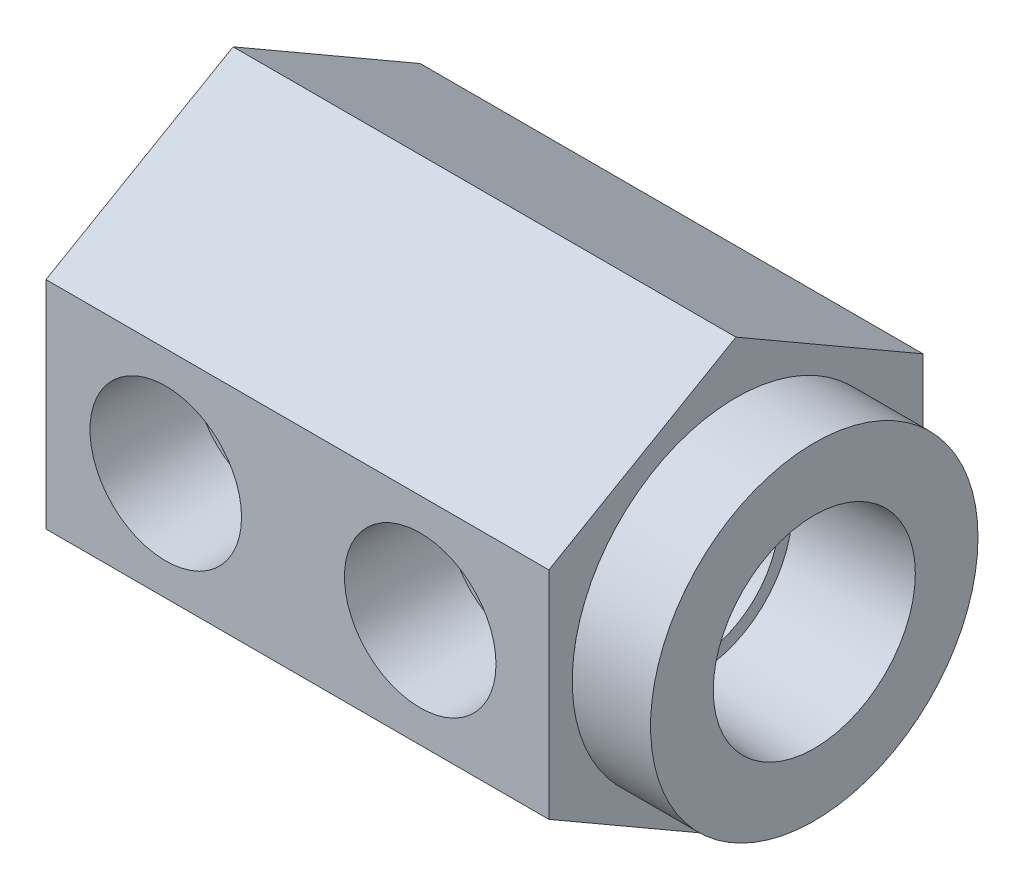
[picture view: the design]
ISO-10303-21;
HEADER;
FILE_DESCRIPTION(('STEP AP214'),'2;1');
FILE_NAME('part.step','',(''),(''),'','','');
FILE_SCHEMA(('AUTOMOTIVE_DESIGN { 1 0 10303 214 1 1 1 1 }'));
ENDSEC;
DATA;
#1=APPLICATION_CONTEXT('core data for automotive mechanical design processes');
#2=APPLICATION_PROTOCOL_DEFINITION('international standard','automotive_design',2000,#1);
#3=PRODUCT_CONTEXT('',#1,'mechanical');
#4=PRODUCT('Part','Part','',(#3));
#5=PRODUCT_RELATED_PRODUCT_CATEGORY('part','',(#4));
#6=PRODUCT_DEFINITION_FORMATION('','',#4);
#7=PRODUCT_DEFINITION_CONTEXT('part definition',#1,'design');
#8=PRODUCT_DEFINITION('design','',#6,#7);
#9=PRODUCT_DEFINITION_SHAPE('','',#8);
#10=(LENGTH_UNIT() NAMED_UNIT(*) SI_UNIT(.MILLI.,.METRE.));
#11=(NAMED_UNIT(*) PLANE_ANGLE_UNIT() SI_UNIT($,.RADIAN.));
#12=(NAMED_UNIT(*) SI_UNIT($,.STERADIAN.) SOLID_ANGLE_UNIT());
#13=UNCERTAINTY_MEASURE_WITH_UNIT(LENGTH_MEASURE(1.E-05),#10,'distance_accuracy_value','');
#14=(GEOMETRIC_REPRESENTATION_CONTEXT(3) GLOBAL_UNCERTAINTY_ASSIGNED_CONTEXT((#13)) GLOBAL_UNIT_ASSIGNED_CONTEXT((#10,
#11,#12)) REPRESENTATION_CONTEXT('',''));
#15=CARTESIAN_POINT('',(0.,0.,0.));
#16=DIRECTION('',(0.,0.,1.));
#17=DIRECTION('',(1.,0.,0.));
#18=AXIS2_PLACEMENT_3D('',#15,#16,#17);
#19=CARTESIAN_POINT('',(39.44747,0.,0.));
#20=DIRECTION('',(1.,0.,0.));
#21=DIRECTION('',(0.,0.,-1.));
#22=AXIS2_PLACEMENT_3D('',#19,#20,#21);
#23=PLANE('',#22);
#24=CARTESIAN_POINT('',(39.44747,0.,0.));
#25=DIRECTION('',(1.,0.,0.));
#26=DIRECTION('',(0.,0.,-1.));
#27=AXIS2_PLACEMENT_3D('',#24,#25,#26);
#28=CIRCLE('',#27,11.1125);
#29=CARTESIAN_POINT('',(39.44747,0.,-11.1125));
#30=VERTEX_POINT('',#29);
#31=EDGE_CURVE('E137',#30,#30,#28,.T.);
#32=ORIENTED_EDGE('',*,*,#31,.T.);
#33=EDGE_LOOP('',(#32));
#34=FACE_BOUND('',#33,.T.);
#35=CARTESIAN_POINT('',(39.44747,0.,0.));
#36=DIRECTION('',(-1.,0.,0.));
#37=DIRECTION('',(0.,0.,1.));
#38=AXIS2_PLACEMENT_3D('',#35,#36,#37);
#39=CIRCLE('',#38,6.85806655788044);
#40=CARTESIAN_POINT('',(39.44747,0.,6.85806655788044));
#41=VERTEX_POINT('',#40);
#42=EDGE_CURVE('E292',#41,#41,#39,.T.);
#43=ORIENTED_EDGE('',*,*,#42,.T.);
#44=EDGE_LOOP('',(#43));
#45=FACE_BOUND('',#44,.T.);
#46=ADVANCED_FACE('F35',(#34,#45),#23,.T.);
#47=CARTESIAN_POINT('',(34.13125,-7.33234841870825,12.7));
#48=DIRECTION('',(1.,0.,0.));
#49=DIRECTION('',(0.,0.,-1.));
#50=AXIS2_PLACEMENT_3D('',#47,#48,#49);
#51=PLANE('',#50);
#52=DIRECTION('',(0.,-1.,0.));
#53=VECTOR('',#52,1.);
#54=CARTESIAN_POINT('',(34.13125,7.33234841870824,12.7));
#55=LINE('',#54,#53);
#56=CARTESIAN_POINT('',(34.13125,7.33234841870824,12.7));
#57=VERTEX_POINT('',#56);
#58=CARTESIAN_POINT('',(34.13125,-7.33234841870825,12.7));
#59=VERTEX_POINT('',#58);
#60=EDGE_CURVE('E145',#57,#59,#55,.T.);
#61=ORIENTED_EDGE('',*,*,#60,.T.);
#62=DIRECTION('',(0.,-0.5,-0.866025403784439));
#63=VECTOR('',#62,1.);
#64=CARTESIAN_POINT('',(34.13125,-7.33234841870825,12.7));
#65=LINE('',#64,#63);
#66=CARTESIAN_POINT('',(34.13125,-14.6646968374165,0.));
#67=VERTEX_POINT('',#66);
#68=EDGE_CURVE('E95',#59,#67,#65,.T.);
#69=ORIENTED_EDGE('',*,*,#68,.T.);
#70=DIRECTION('',(0.,0.5,-0.866025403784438));
#71=VECTOR('',#70,1.);
#72=CARTESIAN_POINT('',(34.13125,-14.6646968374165,0.));
#73=LINE('',#72,#71);
#74=CARTESIAN_POINT('',(34.13125,-7.33234841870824,-12.7));
#75=VERTEX_POINT('',#74);
#76=EDGE_CURVE('E112',#67,#75,#73,.T.);
#77=ORIENTED_EDGE('',*,*,#76,.T.);
#78=DIRECTION('',(0.,1.,0.));
#79=VECTOR('',#78,1.);
#80=CARTESIAN_POINT('',(34.13125,-7.33234841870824,-12.7));
#81=LINE('',#80,#79);
#82=CARTESIAN_POINT('',(34.13125,7.33234841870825,-12.7));
#83=VERTEX_POINT('',#82);
#84=EDGE_CURVE('E104',#75,#83,#81,.T.);
#85=ORIENTED_EDGE('',*,*,#84,.T.);
#86=DIRECTION('',(0.,0.5,0.866025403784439));
#87=VECTOR('',#86,1.);
#88=CARTESIAN_POINT('',(34.13125,7.33234841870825,-12.7));
#89=LINE('',#88,#87);
#90=CARTESIAN_POINT('',(34.13125,14.6646968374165,0.));
#91=VERTEX_POINT('',#90);
#92=EDGE_CURVE('E109',#83,#91,#89,.T.);
#93=ORIENTED_EDGE('',*,*,#92,.T.);
#94=DIRECTION('',(0.,-0.5,0.866025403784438));
#95=VECTOR('',#94,1.);
#96=CARTESIAN_POINT('',(34.13125,14.6646968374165,0.));
#97=LINE('',#96,#95);
#98=EDGE_CURVE('E59',#91,#57,#97,.T.);
#99=ORIENTED_EDGE('',*,*,#98,.T.);
#100=EDGE_LOOP('',(#61,#69,#77,#85,#93,#99));
#101=FACE_BOUND('',#100,.T.);
#102=CARTESIAN_POINT('',(34.13125,0.,0.));
#103=DIRECTION('',(1.,0.,0.));
#104=DIRECTION('',(0.,0.,-1.));
#105=AXIS2_PLACEMENT_3D('',#102,#103,#104);
#106=CIRCLE('',#105,11.1125);
#107=CARTESIAN_POINT('',(34.13125,0.,-11.1125));
#108=VERTEX_POINT('',#107);
#109=EDGE_CURVE('E285',#108,#108,#106,.T.);
#110=ORIENTED_EDGE('',*,*,#109,.F.);
#111=EDGE_LOOP('',(#110));
#112=FACE_BOUND('',#111,.T.);
#113=ADVANCED_FACE('F106',(#101,#112),#51,.T.);
#114=CARTESIAN_POINT('',(34.13125,7.33234841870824,12.7));
#115=DIRECTION('',(0.,0.,-1.));
#116=DIRECTION('',(0.,1.,0.));
#117=AXIS2_PLACEMENT_3D('',#114,#115,#116);
#118=PLANE('',#117);
#119=CARTESIAN_POINT('',(8.128,0.,12.7));
#120=DIRECTION('',(0.,0.,1.));
#121=DIRECTION('',(1.,0.,0.));
#122=AXIS2_PLACEMENT_3D('',#119,#120,#121);
#123=CIRCLE('',#122,5.1435);
#124=CARTESIAN_POINT('',(13.2715,0.,12.7));
#125=VERTEX_POINT('',#124);
#126=EDGE_CURVE('E314',#125,#125,#123,.T.);
#127=ORIENTED_EDGE('',*,*,#126,.F.);
#128=EDGE_LOOP('',(#127));
#129=FACE_BOUND('',#128,.T.);
#130=CARTESIAN_POINT('',(25.4,0.,12.7));
#131=DIRECTION('',(0.,0.,1.));
#132=DIRECTION('',(1.,0.,0.));
#133=AXIS2_PLACEMENT_3D('',#130,#131,#132);
#134=CIRCLE('',#133,5.1435);
#135=CARTESIAN_POINT('',(30.5435,0.,12.7));
#136=VERTEX_POINT('',#135);
#137=EDGE_CURVE('E305',#136,#136,#134,.T.);
#138=ORIENTED_EDGE('',*,*,#137,.F.);
#139=EDGE_LOOP('',(#138));
#140=FACE_BOUND('',#139,.T.);
#141=DIRECTION('',(0.,-1.,0.));
#142=VECTOR('',#141,1.);
#143=CARTESIAN_POINT('',(0.,7.33234841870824,12.7));
#144=LINE('',#143,#142);
#145=CARTESIAN_POINT('',(0.,7.33234841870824,12.7));
#146=VERTEX_POINT('',#145);
#147=CARTESIAN_POINT('',(0.,-7.33234841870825,12.7));
#148=VERTEX_POINT('',#147);
#149=EDGE_CURVE('E133',#146,#148,#144,.T.);
#150=ORIENTED_EDGE('',*,*,#149,.T.);
#151=DIRECTION('',(-1.,0.,0.));
#152=VECTOR('',#151,1.);
#153=CARTESIAN_POINT('',(34.13125,-7.33234841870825,12.7));
#154=LINE('',#153,#152);
#155=EDGE_CURVE('E152',#59,#148,#154,.T.);
#156=ORIENTED_EDGE('',*,*,#155,.F.);
#157=ORIENTED_EDGE('',*,*,#60,.F.);
#158=DIRECTION('',(-1.,0.,0.));
#159=VECTOR('',#158,1.);
#160=CARTESIAN_POINT('',(34.13125,7.33234841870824,12.7));
#161=LINE('',#160,#159);
#162=EDGE_CURVE('E129',#57,#146,#161,.T.);
#163=ORIENTED_EDGE('',*,*,#162,.T.);
#164=EDGE_LOOP('',(#150,#156,#157,#163));
#165=FACE_BOUND('',#164,.T.);
#166=ADVANCED_FACE('F37',(#129,#140,#165),#118,.F.);
#167=CARTESIAN_POINT('',(34.13125,-7.33234841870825,12.7));
#168=DIRECTION('',(0.,0.866025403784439,-0.5));
#169=DIRECTION('',(0.,0.5,0.866025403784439));
#170=AXIS2_PLACEMENT_3D('',#167,#168,#169);
#171=PLANE('',#170);
#172=DIRECTION('',(0.,-0.5,-0.866025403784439));
#173=VECTOR('',#172,1.);
#174=CARTESIAN_POINT('',(0.,-7.33234841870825,12.7));
#175=LINE('',#174,#173);
#176=CARTESIAN_POINT('',(0.,-14.6646968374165,0.));
#177=VERTEX_POINT('',#176);
#178=EDGE_CURVE('E136',#148,#177,#175,.T.);
#179=ORIENTED_EDGE('',*,*,#178,.T.);
#180=DIRECTION('',(-1.,0.,0.));
#181=VECTOR('',#180,1.);
#182=CARTESIAN_POINT('',(34.13125,-14.6646968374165,0.));
#183=LINE('',#182,#181);
#184=EDGE_CURVE('E149',#67,#177,#183,.T.);
#185=ORIENTED_EDGE('',*,*,#184,.F.);
#186=ORIENTED_EDGE('',*,*,#68,.F.);
#187=ORIENTED_EDGE('',*,*,#155,.T.);
#188=EDGE_LOOP('',(#179,#185,#186,#187));
#189=FACE_BOUND('',#188,.T.);
#190=ADVANCED_FACE('F270',(#189),#171,.F.);
#191=CARTESIAN_POINT('',(34.13125,-14.6646968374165,0.));
#192=DIRECTION('',(0.,0.866025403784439,0.5));
#193=DIRECTION('',(0.,-0.5,0.866025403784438));
#194=AXIS2_PLACEMENT_3D('',#191,#192,#193);
#195=PLANE('',#194);
#196=DIRECTION('',(0.,0.5,-0.866025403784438));
#197=VECTOR('',#196,1.);
#198=CARTESIAN_POINT('',(0.,-14.6646968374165,0.));
#199=LINE('',#198,#197);
#200=CARTESIAN_POINT('',(0.,-7.33234841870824,-12.7));
#201=VERTEX_POINT('',#200);
#202=EDGE_CURVE('E139',#177,#201,#199,.T.);
#203=ORIENTED_EDGE('',*,*,#202,.T.);
#204=DIRECTION('',(-1.,0.,0.));
#205=VECTOR('',#204,1.);
#206=CARTESIAN_POINT('',(34.13125,-7.33234841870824,-12.7));
#207=LINE('',#206,#205);
#208=EDGE_CURVE('E124',#75,#201,#207,.T.);
#209=ORIENTED_EDGE('',*,*,#208,.F.);
#210=ORIENTED_EDGE('',*,*,#76,.F.);
#211=ORIENTED_EDGE('',*,*,#184,.T.);
#212=EDGE_LOOP('',(#203,#209,#210,#211));
#213=FACE_BOUND('',#212,.T.);
#214=ADVANCED_FACE('F267',(#213),#195,.F.);
#215=CARTESIAN_POINT('',(34.13125,-7.33234841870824,-12.7));
#216=DIRECTION('',(0.,0.,1.));
#217=DIRECTION('',(0.,-1.,0.));
#218=AXIS2_PLACEMENT_3D('',#215,#216,#217);
#219=PLANE('',#218);
#220=CARTESIAN_POINT('',(8.128,0.,-12.7));
#221=DIRECTION('',(0.,0.,-1.));
#222=DIRECTION('',(0.,1.,0.));
#223=AXIS2_PLACEMENT_3D('',#220,#221,#222);
#224=CIRCLE('',#223,5.1435);
#225=CARTESIAN_POINT('',(8.128,5.1435,-12.7));
#226=VERTEX_POINT('',#225);
#227=EDGE_CURVE('E323',#226,#226,#224,.T.);
#228=ORIENTED_EDGE('',*,*,#227,.F.);
#229=EDGE_LOOP('',(#228));
#230=FACE_BOUND('',#229,.T.);
#231=DIRECTION('',(0.,1.,0.));
#232=VECTOR('',#231,1.);
#233=CARTESIAN_POINT('',(0.,-7.33234841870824,-12.7));
#234=LINE('',#233,#232);
#235=CARTESIAN_POINT('',(0.,7.33234841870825,-12.7));
#236=VERTEX_POINT('',#235);
#237=EDGE_CURVE('E121',#201,#236,#234,.T.);
#238=ORIENTED_EDGE('',*,*,#237,.T.);
#239=DIRECTION('',(-1.,0.,0.));
#240=VECTOR('',#239,1.);
#241=CARTESIAN_POINT('',(34.13125,7.33234841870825,-12.7));
#242=LINE('',#241,#240);
#243=EDGE_CURVE('E118',#83,#236,#242,.T.);
#244=ORIENTED_EDGE('',*,*,#243,.F.);
#245=ORIENTED_EDGE('',*,*,#84,.F.);
#246=ORIENTED_EDGE('',*,*,#208,.T.);
#247=EDGE_LOOP('',(#238,#244,#245,#246));
#248=FACE_BOUND('',#247,.T.);
#249=ADVANCED_FACE('F119',(#230,#248),#219,.F.);
#250=CARTESIAN_POINT('',(34.13125,7.33234841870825,-12.7));
#251=DIRECTION('',(0.,-0.866025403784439,0.5));
#252=DIRECTION('',(0.,-0.5,-0.866025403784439));
#253=AXIS2_PLACEMENT_3D('',#250,#251,#252);
#254=PLANE('',#253);
#255=DIRECTION('',(0.,0.5,0.866025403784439));
#256=VECTOR('',#255,1.);
#257=CARTESIAN_POINT('',(0.,7.33234841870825,-12.7));
#258=LINE('',#257,#256);
#259=CARTESIAN_POINT('',(0.,14.6646968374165,0.));
#260=VERTEX_POINT('',#259);
#261=EDGE_CURVE('E142',#236,#260,#258,.T.);
#262=ORIENTED_EDGE('',*,*,#261,.T.);
#263=DIRECTION('',(-1.,0.,0.));
#264=VECTOR('',#263,1.);
#265=CARTESIAN_POINT('',(34.13125,14.6646968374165,0.));
#266=LINE('',#265,#264);
#267=EDGE_CURVE('E125',#91,#260,#266,.T.);
#268=ORIENTED_EDGE('',*,*,#267,.F.);
#269=ORIENTED_EDGE('',*,*,#92,.F.);
#270=ORIENTED_EDGE('',*,*,#243,.T.);
#271=EDGE_LOOP('',(#262,#268,#269,#270));
#272=FACE_BOUND('',#271,.T.);
#273=ADVANCED_FACE('F127',(#272),#254,.F.);
#274=CARTESIAN_POINT('',(34.13125,14.6646968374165,0.));
#275=DIRECTION('',(0.,-0.866025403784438,-0.5));
#276=DIRECTION('',(0.,0.5,-0.866025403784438));
#277=AXIS2_PLACEMENT_3D('',#274,#275,#276);
#278=PLANE('',#277);
#279=DIRECTION('',(0.,-0.5,0.866025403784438));
#280=VECTOR('',#279,1.);
#281=CARTESIAN_POINT('',(0.,14.6646968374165,0.));
#282=LINE('',#281,#280);
#283=EDGE_CURVE('E86',#260,#146,#282,.T.);
#284=ORIENTED_EDGE('',*,*,#283,.T.);
#285=ORIENTED_EDGE('',*,*,#162,.F.);
#286=ORIENTED_EDGE('',*,*,#98,.F.);
#287=ORIENTED_EDGE('',*,*,#267,.T.);
#288=EDGE_LOOP('',(#284,#285,#286,#287));
#289=FACE_BOUND('',#288,.T.);
#290=ADVANCED_FACE('F259',(#289),#278,.F.);
#291=CARTESIAN_POINT('',(0.,-7.33234841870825,12.7));
#292=DIRECTION('',(1.,0.,0.));
#293=DIRECTION('',(0.,0.,-1.));
#294=AXIS2_PLACEMENT_3D('',#291,#292,#293);
#295=PLANE('',#294);
#296=ORIENTED_EDGE('',*,*,#149,.F.);
#297=ORIENTED_EDGE('',*,*,#283,.F.);
#298=ORIENTED_EDGE('',*,*,#261,.F.);
#299=ORIENTED_EDGE('',*,*,#237,.F.);
#300=ORIENTED_EDGE('',*,*,#202,.F.);
#301=ORIENTED_EDGE('',*,*,#178,.F.);
#302=EDGE_LOOP('',(#296,#297,#298,#299,#300,#301));
#303=FACE_BOUND('',#302,.T.);
#304=ADVANCED_FACE('F254',(#303),#295,.F.);
#305=CARTESIAN_POINT('',(39.44747,0.,0.));
#306=DIRECTION('',(-1.,0.,0.));
#307=DIRECTION('',(0.,0.,1.));
#308=AXIS2_PLACEMENT_3D('',#305,#306,#307);
#309=CYLINDRICAL_SURFACE('',#308,11.1125);
#310=ORIENTED_EDGE('',*,*,#31,.F.);
#311=EDGE_LOOP('',(#310));
#312=FACE_BOUND('',#311,.T.);
#313=ORIENTED_EDGE('',*,*,#109,.T.);
#314=EDGE_LOOP('',(#313));
#315=FACE_BOUND('',#314,.T.);
#316=ADVANCED_FACE('F252',(#312,#315),#309,.T.);
#317=CARTESIAN_POINT('',(31.50997,5.55625,0.));
#318=DIRECTION('',(1.,0.,0.));
#319=DIRECTION('',(0.,0.,-1.));
#320=AXIS2_PLACEMENT_3D('',#317,#318,#319);
#321=PLANE('',#320);
#322=CARTESIAN_POINT('',(31.50997,0.,0.));
#323=DIRECTION('',(-1.,0.,0.));
#324=DIRECTION('',(0.,0.,1.));
#325=AXIS2_PLACEMENT_3D('',#322,#323,#324);
#326=CIRCLE('',#325,5.55625);
#327=CARTESIAN_POINT('',(31.50997,0.,5.55625));
#328=VERTEX_POINT('',#327);
#329=EDGE_CURVE('E162',#328,#328,#326,.T.);
#330=ORIENTED_EDGE('',*,*,#329,.T.);
#331=EDGE_LOOP('',(#330));
#332=FACE_BOUND('',#331,.T.);
#333=CARTESIAN_POINT('',(31.50997,0.,0.));
#334=DIRECTION('',(-1.,0.,0.));
#335=DIRECTION('',(0.,0.,1.));
#336=AXIS2_PLACEMENT_3D('',#333,#334,#335);
#337=CIRCLE('',#336,6.44207980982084);
#338=CARTESIAN_POINT('',(31.50997,0.,6.44207980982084));
#339=VERTEX_POINT('',#338);
#340=EDGE_CURVE('E288',#339,#339,#337,.T.);
#341=ORIENTED_EDGE('',*,*,#340,.F.);
#342=EDGE_LOOP('',(#341));
#343=FACE_BOUND('',#342,.T.);
#344=ADVANCED_FACE('F250',(#332,#343),#321,.T.);
#345=CARTESIAN_POINT('',(39.44747,0.,0.));
#346=DIRECTION('',(1.,0.,0.));
#347=DIRECTION('',(0.,0.,-1.));
#348=AXIS2_PLACEMENT_3D('',#345,#346,#347);
#349=CONICAL_SURFACE('',#348,6.85806655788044,0.0523598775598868);
#350=ORIENTED_EDGE('',*,*,#340,.T.);
#351=EDGE_LOOP('',(#350));
#352=FACE_BOUND('',#351,.T.);
#353=ORIENTED_EDGE('',*,*,#42,.F.);
#354=EDGE_LOOP('',(#353));
#355=FACE_BOUND('',#354,.T.);
#356=ADVANCED_FACE('F350',(#352,#355),#349,.F.);
#357=CARTESIAN_POINT('',(21.03247,0.,0.));
#358=DIRECTION('',(1.,0.,0.));
#359=DIRECTION('',(0.,0.,-1.));
#360=AXIS2_PLACEMENT_3D('',#357,#358,#359);
#361=PLANE('',#360);
#362=CARTESIAN_POINT('',(21.03247,0.,0.));
#363=DIRECTION('',(1.,0.,0.));
#364=DIRECTION('',(0.,0.,-1.));
#365=AXIS2_PLACEMENT_3D('',#362,#363,#364);
#366=CIRCLE('',#365,3.96875);
#367=CARTESIAN_POINT('',(21.03247,0.,-3.96875));
#368=VERTEX_POINT('',#367);
#369=EDGE_CURVE('E39',#368,#368,#366,.T.);
#370=ORIENTED_EDGE('',*,*,#369,.F.);
#371=EDGE_LOOP('',(#370));
#372=FACE_BOUND('',#371,.T.);
#373=CARTESIAN_POINT('',(21.03247,0.,0.));
#374=DIRECTION('',(-1.,0.,0.));
#375=DIRECTION('',(0.,0.,1.));
#376=AXIS2_PLACEMENT_3D('',#373,#374,#375);
#377=CIRCLE('',#376,5.55625);
#378=CARTESIAN_POINT('',(21.03247,0.,5.55625));
#379=VERTEX_POINT('',#378);
#380=EDGE_CURVE('E295',#379,#379,#377,.T.);
#381=ORIENTED_EDGE('',*,*,#380,.F.);
#382=EDGE_LOOP('',(#381));
#383=FACE_BOUND('',#382,.T.);
#384=ADVANCED_FACE('F347',(#372,#383),#361,.T.);
#385=CARTESIAN_POINT('',(0.,0.,0.));
#386=DIRECTION('',(-1.,0.,0.));
#387=DIRECTION('',(0.,0.,1.));
#388=AXIS2_PLACEMENT_3D('',#385,#386,#387);
#389=CYLINDRICAL_SURFACE('',#388,5.55625);
#390=CARTESIAN_POINT('',(29.6164,0.,5.55625));
#391=CARTESIAN_POINT('',(29.6163993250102,-0.102693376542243,5.55624935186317));
#392=CARTESIAN_POINT('',(29.6126418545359,-0.205397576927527,5.55339643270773));
#393=CARTESIAN_POINT('',(29.5976742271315,-0.409987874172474,5.54205114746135));
#394=CARTESIAN_POINT('',(29.586460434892,-0.511873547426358,5.53355603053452));
#395=CARTESIAN_POINT('',(29.5567421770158,-0.714130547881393,5.51110649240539));
#396=CARTESIAN_POINT('',(29.5382264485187,-0.814499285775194,5.49714363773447));
#397=CARTESIAN_POINT('',(29.4942051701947,-1.01284455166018,5.46408215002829));
#398=CARTESIAN_POINT('',(29.4686965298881,-1.11082000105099,5.44498124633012));
#399=CARTESIAN_POINT('',(29.3825831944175,-1.39891797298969,5.38083315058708));
#400=CARTESIAN_POINT('',(29.3121704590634,-1.58466430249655,5.32877063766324));
#401=CARTESIAN_POINT('',(29.1485378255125,-1.94034128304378,5.20982470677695));
#402=CARTESIAN_POINT('',(29.0553219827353,-2.11027473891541,5.1429439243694));
#403=CARTESIAN_POINT('',(28.8395703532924,-2.44767830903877,4.99179767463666));
#404=CARTESIAN_POINT('',(28.7151124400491,-2.61344503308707,4.90649322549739));
#405=CARTESIAN_POINT('',(28.445557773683,-2.92315956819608,4.72852964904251));
#406=CARTESIAN_POINT('',(28.300430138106,-3.06707405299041,4.63585961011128));
#407=CARTESIAN_POINT('',(28.0527623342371,-3.27963118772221,4.48615059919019));
#408=CARTESIAN_POINT('',(27.9560898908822,-3.35552727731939,4.42952031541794));
#409=CARTESIAN_POINT('',(27.7560755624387,-3.49886885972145,4.31718819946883));
#410=CARTESIAN_POINT('',(27.6527316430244,-3.56631175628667,4.26148665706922));
#411=CARTESIAN_POINT('',(27.4395786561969,-3.69235121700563,4.15275532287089));
#412=CARTESIAN_POINT('',(27.3297756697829,-3.75095592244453,4.09972310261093));
#413=CARTESIAN_POINT('',(27.1037486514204,-3.85888092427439,3.99830378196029));
#414=CARTESIAN_POINT('',(26.9875283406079,-3.90820652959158,3.94991403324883));
#415=CARTESIAN_POINT('',(26.7125548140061,-4.01032101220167,3.84655569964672));
#416=CARTESIAN_POINT('',(26.5515353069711,-4.05967723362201,3.79399633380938));
#417=CARTESIAN_POINT('',(26.3032358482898,-4.11939822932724,3.72871892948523));
#418=CARTESIAN_POINT('',(26.2193920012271,-4.13691360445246,3.70922751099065));
#419=CARTESIAN_POINT('',(26.0497879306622,-4.1669184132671,3.67548846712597));
#420=CARTESIAN_POINT('',(25.9640287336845,-4.17941047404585,3.66123810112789));
#421=CARTESIAN_POINT('',(25.7902465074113,-4.19922159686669,3.63850031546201));
#422=CARTESIAN_POINT('',(25.702209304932,-4.20648654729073,3.63007321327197));
#423=CARTESIAN_POINT('',(25.5254696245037,-4.21546136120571,3.61964744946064));
#424=CARTESIAN_POINT('',(25.4367671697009,-4.21717141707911,3.61764856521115));
#425=CARTESIAN_POINT('',(25.25950294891,-4.21499058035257,3.62018953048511));
#426=CARTESIAN_POINT('',(25.1709412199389,-4.21109840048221,3.62473088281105));
#427=CARTESIAN_POINT('',(24.9948050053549,-4.19781579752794,3.64010347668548));
#428=CARTESIAN_POINT('',(24.9072305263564,-4.18842533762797,3.65093476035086));
#429=CARTESIAN_POINT('',(24.6670671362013,-4.15509038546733,3.68893056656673));
#430=CARTESIAN_POINT('',(24.5161923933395,-4.12550713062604,3.72225050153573));
#431=CARTESIAN_POINT('',(24.2220882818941,-4.05137671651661,3.80278947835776));
#432=CARTESIAN_POINT('',(24.0788668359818,-4.00681438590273,3.85002260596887));
#433=CARTESIAN_POINT('',(23.8260179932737,-3.91348438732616,3.94463534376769));
#434=CARTESIAN_POINT('',(23.7149764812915,-3.86690895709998,3.99046546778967));
#435=CARTESIAN_POINT('',(23.4987398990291,-3.76530472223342,4.08647520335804));
#436=CARTESIAN_POINT('',(23.3935479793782,-3.71027142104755,4.13665712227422));
#437=CARTESIAN_POINT('',(23.1888896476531,-3.59207638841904,4.2397008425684));
#438=CARTESIAN_POINT('',(23.0894357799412,-3.52889775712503,4.29256807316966));
#439=CARTESIAN_POINT('',(22.896560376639,-3.39479221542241,4.39939220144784));
#440=CARTESIAN_POINT('',(22.8031378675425,-3.32386656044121,4.45334892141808));
#441=CARTESIAN_POINT('',(22.6198789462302,-3.17229987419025,4.56260828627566));
#442=CARTESIAN_POINT('',(22.5302195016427,-3.09144027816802,4.61790568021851));
#443=CARTESIAN_POINT('',(22.3577105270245,-2.92184039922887,4.72704545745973));
#444=CARTESIAN_POINT('',(22.274863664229,-2.83309705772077,4.78088726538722));
#445=CARTESIAN_POINT('',(22.0375306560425,-2.55557286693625,4.93821773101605));
#446=CARTESIAN_POINT('',(21.893717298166,-2.3550581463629,5.03784133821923));
#447=CARTESIAN_POINT('',(21.6649881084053,-1.96676092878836,5.19991035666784));
#448=CARTESIAN_POINT('',(21.5740623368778,-1.783982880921,5.26582042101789));
#449=CARTESIAN_POINT('',(21.4573057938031,-1.49794068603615,5.35145144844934));
#450=CARTESIAN_POINT('',(21.421651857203,-1.40058567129,5.37779487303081));
#451=CARTESIAN_POINT('',(21.3573496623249,-1.20243166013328,5.42553595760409));
#452=CARTESIAN_POINT('',(21.3286983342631,-1.10163419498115,5.44693578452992));
#453=CARTESIAN_POINT('',(21.2786470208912,-0.896496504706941,5.48444704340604));
#454=CARTESIAN_POINT('',(21.2573003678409,-0.792136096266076,5.50051955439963));
#455=CARTESIAN_POINT('',(21.2225152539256,-0.581416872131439,5.52676517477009));
#456=CARTESIAN_POINT('',(21.2090731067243,-0.475059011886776,5.53694103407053));
#457=CARTESIAN_POINT('',(21.1903325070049,-0.261235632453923,5.55113934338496));
#458=CARTESIAN_POINT('',(21.1850326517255,-0.1537703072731,5.55516285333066));
#459=CARTESIAN_POINT('',(21.1826743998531,0.0612961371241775,5.5569523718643));
#460=CARTESIAN_POINT('',(21.1856152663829,0.168897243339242,5.55471893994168));
#461=CARTESIAN_POINT('',(21.1989208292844,0.371674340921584,5.5446311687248));
#462=CARTESIAN_POINT('',(21.2084499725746,0.466937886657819,5.53740954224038));
#463=CARTESIAN_POINT('',(21.2338694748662,0.656134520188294,5.51819377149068));
#464=CARTESIAN_POINT('',(21.2497618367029,0.750067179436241,5.50619812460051));
#465=CARTESIAN_POINT('',(21.3066724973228,1.0288748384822,5.46338413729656));
#466=CARTESIAN_POINT('',(21.356935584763,1.21092313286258,5.42573004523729));
#467=CARTESIAN_POINT('',(21.4812624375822,1.56789963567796,5.33372302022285));
#468=CARTESIAN_POINT('',(21.5559374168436,1.74249866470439,5.27894302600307));
#469=CARTESIAN_POINT('',(21.7256433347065,2.07659649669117,5.15667714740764));
#470=CARTESIAN_POINT('',(21.8206773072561,2.23609304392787,5.08918936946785));
#471=CARTESIAN_POINT('',(22.0455518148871,2.56347572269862,4.93341300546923));
#472=CARTESIAN_POINT('',(22.1785466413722,2.72842274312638,4.8435290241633));
#473=CARTESIAN_POINT('',(22.4657559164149,3.03521371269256,4.65742624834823));
#474=CARTESIAN_POINT('',(22.6200134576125,3.17700943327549,4.56119480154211));
#475=CARTESIAN_POINT('',(22.8821039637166,3.38436105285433,4.40765179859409));
#476=CARTESIAN_POINT('',(22.9837901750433,3.45770845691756,4.35018681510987));
#477=CARTESIAN_POINT('',(23.1940490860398,3.59549974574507,4.23700773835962));
#478=CARTESIAN_POINT('',(23.3026242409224,3.65994042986,4.18129428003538));
#479=CARTESIAN_POINT('',(23.5263714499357,3.77936334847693,4.07366880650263));
#480=CARTESIAN_POINT('',(23.6415306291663,3.8343632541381,4.02174979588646));
#481=CARTESIAN_POINT('',(23.8784440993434,3.93439147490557,3.92394754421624));
#482=CARTESIAN_POINT('',(24.0001932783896,3.97942738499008,3.8780597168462));
#483=CARTESIAN_POINT('',(24.2790144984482,4.06784554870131,3.78544072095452));
#484=CARTESIAN_POINT('',(24.4377707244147,4.10846555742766,3.74094260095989));
#485=CARTESIAN_POINT('',(24.6813970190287,4.15553716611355,3.6883562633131));
#486=CARTESIAN_POINT('',(24.7634690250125,4.16891399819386,3.67319259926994));
#487=CARTESIAN_POINT('',(24.9290383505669,4.19084532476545,3.64815156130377));
#488=CARTESIAN_POINT('',(25.0125349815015,4.19940208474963,3.63827170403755));
#489=CARTESIAN_POINT('',(25.1809809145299,4.21156059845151,3.62419089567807));
#490=CARTESIAN_POINT('',(25.2659363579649,4.21512601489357,3.62003159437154));
#491=CARTESIAN_POINT('',(25.4359878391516,4.21710364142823,3.61772767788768));
#492=CARTESIAN_POINT('',(25.5210838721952,4.21551602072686,3.61958286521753));
#493=CARTESIAN_POINT('',(25.69074369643,4.20722188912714,3.629219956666));
#494=CARTESIAN_POINT('',(25.7753070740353,4.20051180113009,3.63700600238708));
#495=CARTESIAN_POINT('',(25.9432169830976,4.1821148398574,3.65814491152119));
#496=CARTESIAN_POINT('',(26.0265628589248,4.17042538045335,3.67150066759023));
#497=CARTESIAN_POINT('',(26.2053377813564,4.13992798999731,3.70587659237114));
#498=CARTESIAN_POINT('',(26.3004441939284,4.1202540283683,3.72780747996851));
#499=CARTESIAN_POINT('',(26.4876880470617,4.07483267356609,3.77740472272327));
#500=CARTESIAN_POINT('',(26.5798232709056,4.0490808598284,3.80507525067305));
#501=CARTESIAN_POINT('',(26.8515481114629,3.9632252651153,3.89507311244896));
#502=CARTESIAN_POINT('',(27.0262161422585,3.89456404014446,3.9643352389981));
#503=CARTESIAN_POINT('',(27.3096983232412,3.76132382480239,4.0902354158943));
#504=CARTESIAN_POINT('',(27.4222798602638,3.70195130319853,4.14423023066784));
#505=CARTESIAN_POINT('',(27.6406852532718,3.57398466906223,4.25507997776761));
#506=CARTESIAN_POINT('',(27.7465066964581,3.50538729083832,4.31193591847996));
#507=CARTESIAN_POINT('',(27.9513183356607,3.35926316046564,4.42672704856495));
#508=CARTESIAN_POINT('',(28.0503021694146,3.28172826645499,4.48466318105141));
#509=CARTESIAN_POINT('',(28.2411263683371,3.11798488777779,4.60001225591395));
#510=CARTESIAN_POINT('',(28.332967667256,3.03177754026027,4.65742526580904));
#511=CARTESIAN_POINT('',(28.5103676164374,2.84956733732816,4.77111867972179));
#512=CARTESIAN_POINT('',(28.5958206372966,2.75344451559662,4.82737207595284));
#513=CARTESIAN_POINT('',(28.7584200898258,2.55259396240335,4.93652120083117));
#514=CARTESIAN_POINT('',(28.8355654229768,2.44786509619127,4.98941648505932));
#515=CARTESIAN_POINT('',(28.9806112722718,2.23031622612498,5.09037894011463));
#516=CARTESIAN_POINT('',(29.048528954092,2.11751185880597,5.13845503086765));
#517=CARTESIAN_POINT('',(29.1743228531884,1.88416115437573,5.22852473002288));
#518=CARTESIAN_POINT('',(29.232203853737,1.76361854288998,5.27052123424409));
#519=CARTESIAN_POINT('',(29.3221097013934,1.55061985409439,5.3363074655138));
#520=CARTESIAN_POINT('',(29.3568210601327,1.45984111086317,5.36189016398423));
#521=CARTESIAN_POINT('',(29.420152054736,1.27512063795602,5.40879414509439));
#522=CARTESIAN_POINT('',(29.448773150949,1.18117967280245,5.43011644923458));
#523=CARTESIAN_POINT('',(29.4995054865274,0.990840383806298,5.46804785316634));
#524=CARTESIAN_POINT('',(29.5216302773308,0.894447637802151,5.48466676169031));
#525=CARTESIAN_POINT('',(29.5591251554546,0.699668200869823,5.51289892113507));
#526=CARTESIAN_POINT('',(29.5744981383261,0.601282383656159,5.52451431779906));
#527=CARTESIAN_POINT('',(29.5963476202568,0.419165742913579,5.54104473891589));
#528=CARTESIAN_POINT('',(29.6038584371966,0.335627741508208,5.54673779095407));
#529=CARTESIAN_POINT('',(29.6138854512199,0.168062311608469,5.55434110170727));
#530=CARTESIAN_POINT('',(29.6164005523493,0.0840347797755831,5.55625053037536));
#531=CARTESIAN_POINT('',(29.6164,0.,5.55625));
#532=B_SPLINE_CURVE_WITH_KNOTS('',3,(#390,#391,#392,#393,#394,#395,#396,#397,#398,#399,#400,
#401,#402,#403,#404,#405,#406,#407,#408,#409,#410,#411,#412,#413,#414,#415,#416,#417,#418,#419,
#420,#421,#422,#423,#424,#425,#426,#427,#428,#429,#430,#431,#432,#433,#434,#435,#436,#437,#438,
#439,#440,#441,#442,#443,#444,#445,#446,#447,#448,#449,#450,#451,#452,#453,#454,#455,#456,#457,
#458,#459,#460,#461,#462,#463,#464,#465,#466,#467,#468,#469,#470,#471,#472,#473,#474,#475,#476,
#477,#478,#479,#480,#481,#482,#483,#484,#485,#486,#487,#488,#489,#490,#491,#492,#493,#494,#495,
#496,#497,#498,#499,#500,#501,#502,#503,#504,#505,#506,#507,#508,#509,#510,#511,#512,#513,#514,
#515,#516,#517,#518,#519,#520,#521,#522,#523,#524,#525,#526,#527,#528,#529,#530,#531),
.UNSPECIFIED.,.T.,.F.,(4,2,2,2,2,2,2,2,2,2,2,2,2,2,2,2,2,2,2,2,2,2,2,2,2,2,2,2,2,2,2,2,2,2,2,2,
2,2,2,2,2,2,2,2,2,2,2,2,2,2,2,2,2,2,2,2,2,2,2,2,2,2,2,2,2,2,2,2,2,2,4),(0.,0.307991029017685,
0.616132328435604,0.924750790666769,1.2335058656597,1.84663803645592,2.459661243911,
3.12977733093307,3.80090534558,4.20650775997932,4.61223444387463,5.01758508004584,
5.42270308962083,5.94985658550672,6.21312560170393,6.47625675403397,6.74207413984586,
7.00788231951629,7.27375158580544,7.53962263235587,8.00965097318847,8.48015681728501,
8.86617029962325,9.25238971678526,9.63942375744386,10.0263951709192,10.4243466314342,
10.8224531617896,11.6163911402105,12.2571875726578,12.5777622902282,12.8981962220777,
13.2209221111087,13.5434973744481,13.8660170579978,14.1885079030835,14.4761906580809,
14.7639640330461,15.3390242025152,15.9297539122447,16.5205717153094,17.2086216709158,
17.8980871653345,18.3114499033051,18.7249608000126,19.1376890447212,19.5501015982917,
20.057359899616,20.3106781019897,20.563877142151,20.8189100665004,21.0739346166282,
21.3291374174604,21.5844729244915,21.8827088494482,22.1811623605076,22.7788098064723,
23.1931606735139,23.6076586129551,24.0225371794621,24.4373614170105,24.857977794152,
25.2786497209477,25.6985280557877,26.118205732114,26.4194112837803,26.720544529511,
27.021045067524,27.3214166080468,27.5733927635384,27.8254241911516),.UNSPECIFIED.);
#533=CARTESIAN_POINT('',(29.6164,0.,5.55625));
#534=VERTEX_POINT('',#533);
#535=EDGE_CURVE('E155',#534,#534,#532,.T.);
#536=ORIENTED_EDGE('',*,*,#535,.F.);
#537=EDGE_LOOP('',(#536));
#538=FACE_BOUND('',#537,.T.);
#539=ORIENTED_EDGE('',*,*,#380,.T.);
#540=EDGE_LOOP('',(#539));
#541=FACE_BOUND('',#540,.T.);
#542=ORIENTED_EDGE('',*,*,#329,.F.);
#543=EDGE_LOOP('',(#542));
#544=FACE_BOUND('',#543,.T.);
#545=ADVANCED_FACE('F170',(#538,#541,#544),#389,.F.);
#546=CARTESIAN_POINT('',(25.4,0.,12.7));
#547=DIRECTION('',(0.,0.,1.));
#548=DIRECTION('',(1.,0.,0.));
#549=AXIS2_PLACEMENT_3D('',#546,#547,#548);
#550=CYLINDRICAL_SURFACE('',#549,4.2164);
#551=ORIENTED_EDGE('',*,*,#535,.T.);
#552=EDGE_LOOP('',(#551));
#553=FACE_BOUND('',#552,.T.);
#554=CARTESIAN_POINT('',(25.4,0.,5.77596));
#555=DIRECTION('',(0.,0.,1.));
#556=DIRECTION('',(1.,0.,0.));
#557=AXIS2_PLACEMENT_3D('',#554,#555,#556);
#558=CIRCLE('',#557,4.2164);
#559=CARTESIAN_POINT('',(29.6164,0.,5.77596));
#560=VERTEX_POINT('',#559);
#561=EDGE_CURVE('E163',#560,#560,#558,.T.);
#562=ORIENTED_EDGE('',*,*,#561,.T.);
#563=EDGE_LOOP('',(#562));
#564=FACE_BOUND('',#563,.T.);
#565=ADVANCED_FACE('F173',(#553,#564),#550,.F.);
#566=CARTESIAN_POINT('',(29.6164,0.,5.77596));
#567=DIRECTION('',(0.,0.,-1.));
#568=DIRECTION('',(-1.,0.,0.));
#569=AXIS2_PLACEMENT_3D('',#566,#567,#568);
#570=PLANE('',#569);
#571=ORIENTED_EDGE('',*,*,#561,.F.);
#572=EDGE_LOOP('',(#571));
#573=FACE_BOUND('',#572,.T.);
#574=CARTESIAN_POINT('',(25.4,0.,5.77596));
#575=DIRECTION('',(0.,0.,1.));
#576=DIRECTION('',(1.,0.,0.));
#577=AXIS2_PLACEMENT_3D('',#574,#575,#576);
#578=CIRCLE('',#577,4.93618496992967);
#579=CARTESIAN_POINT('',(30.3361849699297,0.,5.77596));
#580=VERTEX_POINT('',#579);
#581=EDGE_CURVE('E302',#580,#580,#578,.T.);
#582=ORIENTED_EDGE('',*,*,#581,.T.);
#583=EDGE_LOOP('',(#582));
#584=FACE_BOUND('',#583,.T.);
#585=ADVANCED_FACE('F177',(#573,#584),#570,.F.);
#586=CARTESIAN_POINT('',(25.4,0.,12.7));
#587=DIRECTION('',(0.,0.,1.));
#588=DIRECTION('',(1.,0.,0.));
#589=AXIS2_PLACEMENT_3D('',#586,#587,#588);
#590=CONICAL_SURFACE('',#589,5.1435,0.0299323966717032);
#591=ORIENTED_EDGE('',*,*,#581,.F.);
#592=EDGE_LOOP('',(#591));
#593=FACE_BOUND('',#592,.T.);
#594=ORIENTED_EDGE('',*,*,#137,.T.);
#595=EDGE_LOOP('',(#594));
#596=FACE_BOUND('',#595,.T.);
#597=ADVANCED_FACE('F181',(#593,#596),#590,.F.);
#598=CARTESIAN_POINT('',(8.128,0.,12.7));
#599=DIRECTION('',(0.,0.,1.));
#600=DIRECTION('',(1.,0.,0.));
#601=AXIS2_PLACEMENT_3D('',#598,#599,#600);
#602=CYLINDRICAL_SURFACE('',#601,4.2164);
#603=CARTESIAN_POINT('',(10.86993,-3.20309987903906,-1.29345681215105));
#604=CARTESIAN_POINT('',(10.8935842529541,-3.18285348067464,-1.34358685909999));
#605=CARTESIAN_POINT('',(10.9179308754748,-3.16155586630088,-1.39294673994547));
#606=CARTESIAN_POINT('',(10.9677116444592,-3.11691854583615,-1.49015514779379));
#607=CARTESIAN_POINT('',(10.9931455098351,-3.09357936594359,-1.53800405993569));
#608=CARTESIAN_POINT('',(11.0706135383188,-3.02060903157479,-1.67929702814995));
#609=CARTESIAN_POINT('',(11.1238495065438,-2.96799537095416,-1.7705603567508));
#610=CARTESIAN_POINT('',(11.2321253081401,-2.85458341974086,-1.94818870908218));
#611=CARTESIAN_POINT('',(11.2871773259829,-2.79371344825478,-2.03450018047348));
#612=CARTESIAN_POINT('',(11.3970908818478,-2.66426087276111,-2.20130360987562));
#613=CARTESIAN_POINT('',(11.4519523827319,-2.59567684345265,-2.28179448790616));
#614=CARTESIAN_POINT('',(11.5601067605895,-2.45088443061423,-2.43665194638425));
#615=CARTESIAN_POINT('',(11.613400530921,-2.37468050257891,-2.51102205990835));
#616=CARTESIAN_POINT('',(11.717215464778,-2.21464671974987,-2.65323907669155));
#617=CARTESIAN_POINT('',(11.7677365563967,-2.1308166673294,-2.72108581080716));
#618=CARTESIAN_POINT('',(11.8645907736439,-1.95598050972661,-2.84933666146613));
#619=CARTESIAN_POINT('',(11.9109398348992,-1.86500443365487,-2.90976944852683));
#620=CARTESIAN_POINT('',(11.9984216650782,-1.6759239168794,-3.02262836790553));
#621=CARTESIAN_POINT('',(12.0395569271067,-1.57782291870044,-3.07505832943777));
#622=CARTESIAN_POINT('',(12.1298545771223,-1.33623044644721,-3.18925433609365));
#623=CARTESIAN_POINT('',(12.176113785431,-1.18967340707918,-3.24697940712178));
#624=CARTESIAN_POINT('',(12.2531511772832,-0.886345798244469,-3.34253208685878));
#625=CARTESIAN_POINT('',(12.2839378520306,-0.729580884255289,-3.38037060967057));
#626=CARTESIAN_POINT('',(12.327647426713,-0.408975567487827,-3.43396772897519));
#627=CARTESIAN_POINT('',(12.3404798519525,-0.245103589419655,-3.44961450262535));
#628=CARTESIAN_POINT('',(12.346772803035,0.0835656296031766,-3.45729674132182));
#629=CARTESIAN_POINT('',(12.3402360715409,0.248362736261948,-3.44933554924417));
#630=CARTESIAN_POINT('',(12.3097062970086,0.560344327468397,-3.41198152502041));
#631=CARTESIAN_POINT('',(12.2871409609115,0.70788809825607,-3.38434112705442));
#632=CARTESIAN_POINT('',(12.2278444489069,0.99542509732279,-3.31119780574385));
#633=CARTESIAN_POINT('',(12.1911127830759,1.13541806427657,-3.26569426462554));
#634=CARTESIAN_POINT('',(12.1030918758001,1.41398661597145,-3.15553154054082));
#635=CARTESIAN_POINT('',(12.051022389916,1.55190001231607,-3.08983411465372));
#636=CARTESIAN_POINT('',(11.9365869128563,1.81475019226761,-2.94317375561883));
#637=CARTESIAN_POINT('',(11.8742086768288,1.93967125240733,-2.8621926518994));
#638=CARTESIAN_POINT('',(11.7116860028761,2.23029122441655,-2.64666794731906));
#639=CARTESIAN_POINT('',(11.6073950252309,2.38821403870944,-2.50464969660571));
#640=CARTESIAN_POINT('',(11.4467050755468,2.60235561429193,-2.27412521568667));
#641=CARTESIAN_POINT('',(11.3923963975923,2.66998200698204,-2.19431033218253));
#642=CARTESIAN_POINT('',(11.2836244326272,2.79769102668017,-2.02896671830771));
#643=CARTESIAN_POINT('',(11.2291612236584,2.85777694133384,-1.94344050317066));
#644=CARTESIAN_POINT('',(11.121799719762,2.97005001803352,-1.7670784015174));
#645=CARTESIAN_POINT('',(11.0688955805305,3.02227086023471,-1.67626760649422));
#646=CARTESIAN_POINT('',(10.9919974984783,3.09463803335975,-1.53585638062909));
#647=CARTESIAN_POINT('',(10.9668060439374,3.11773990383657,-1.48841865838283));
#648=CARTESIAN_POINT('',(10.917492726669,3.16193913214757,-1.39205849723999));
#649=CARTESIAN_POINT('',(10.8933711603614,3.18303593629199,-1.34313565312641));
#650=CARTESIAN_POINT('',(10.86993,3.20309987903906,-1.29345681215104));
#651=B_SPLINE_CURVE_WITH_KNOTS('',3,(#603,#604,#605,#606,#607,#608,#609,#610,#611,#612,#613,
#614,#615,#616,#617,#618,#619,#620,#621,#622,#623,#624,#625,#626,#627,#628,#629,#630,#631,#632,
#633,#634,#635,#636,#637,#638,#639,#640,#641,#642,#643,#644,#645,#646,#647,#648,#649,#650),
.UNSPECIFIED.,.F.,.F.,(4,2,2,2,2,2,2,2,2,2,2,2,2,2,2,2,2,2,2,2,2,2,2,4),(0.,0.176991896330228,
0.353938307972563,0.707572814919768,1.06450173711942,1.42149671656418,1.77828416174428,
2.13508085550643,2.49045110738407,2.84565078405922,3.33603334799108,3.82614649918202,
4.31872063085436,4.81122501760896,5.26461214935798,5.71801496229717,6.20039014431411,
6.68334247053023,7.38910669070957,7.74244544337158,8.09562960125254,8.44725548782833,
8.62260738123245,8.79800755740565),.UNSPECIFIED.);
#652=CARTESIAN_POINT('',(10.86993,-3.20309987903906,-1.29345681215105));
#653=VERTEX_POINT('',#652);
#654=CARTESIAN_POINT('',(10.86993,3.20309987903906,-1.29345681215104));
#655=VERTEX_POINT('',#654);
#656=EDGE_CURVE('E44',#653,#655,#651,.T.);
#657=ORIENTED_EDGE('',*,*,#656,.T.);
#658=CARTESIAN_POINT('',(11.0776912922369,3.01286412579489,-2.316023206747));
#659=CARTESIAN_POINT('',(11.0570644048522,3.03305702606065,-2.23342246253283));
#660=CARTESIAN_POINT('',(11.0371654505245,3.05212528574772,-2.15036237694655));
#661=CARTESIAN_POINT('',(10.9990311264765,3.08802482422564,-1.98339698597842));
#662=CARTESIAN_POINT('',(10.9807954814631,3.10485647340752,-1.89949182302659));
#663=CARTESIAN_POINT('',(10.9461679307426,3.13632048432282,-1.73078200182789));
#664=CARTESIAN_POINT('',(10.9297782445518,3.15095020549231,-1.64597639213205));
#665=CARTESIAN_POINT('',(10.8990695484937,3.17798993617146,-1.47561970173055));
#666=CARTESIAN_POINT('',(10.8847510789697,3.19039936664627,-1.39006843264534));
#667=CARTESIAN_POINT('',(10.845926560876,3.22367115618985,-1.13709280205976));
#668=CARTESIAN_POINT('',(10.824590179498,3.24143055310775,-0.968745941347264));
#669=CARTESIAN_POINT('',(10.791837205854,3.26840309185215,-0.630405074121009));
#670=CARTESIAN_POINT('',(10.7804198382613,3.27761690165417,-0.460411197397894));
#671=CARTESIAN_POINT('',(10.7704653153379,3.28563876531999,-0.18157883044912));
#672=CARTESIAN_POINT('',(10.7687589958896,3.28700847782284,-0.0729151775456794));
#673=CARTESIAN_POINT('',(10.7697144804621,3.28623956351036,0.144382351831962));
#674=CARTESIAN_POINT('',(10.7723764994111,3.28410076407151,0.253016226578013));
#675=CARTESIAN_POINT('',(10.7868514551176,3.27242061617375,0.578652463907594));
#676=CARTESIAN_POINT('',(10.8051591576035,3.257610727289,0.795222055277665));
#677=CARTESIAN_POINT('',(10.8580733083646,3.21339785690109,1.2325203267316));
#678=CARTESIAN_POINT('',(10.8932251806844,3.18350461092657,1.45313117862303));
#679=CARTESIAN_POINT('',(10.9557482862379,3.12772080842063,1.78000252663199));
#680=CARTESIAN_POINT('',(10.9782011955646,3.10732177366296,1.88820517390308));
#681=CARTESIAN_POINT('',(11.0259337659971,3.06285328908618,2.10319361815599));
#682=CARTESIAN_POINT('',(11.0512126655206,3.03878482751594,2.20997978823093));
#683=CARTESIAN_POINT('',(11.0776912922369,3.01286412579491,2.31602320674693));
#684=B_SPLINE_CURVE_WITH_KNOTS('',3,(#658,#659,#660,#661,#662,#663,#664,#665,#666,#667,#668,
#669,#670,#671,#672,#673,#674,#675,#676,#677,#678,#679,#680,#681,#682,#683),.UNSPECIFIED.,.F.,
.F.,(4,2,2,2,2,2,2,2,2,2,2,2,4),(0.,0.262489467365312,0.524935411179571,0.787693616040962,
1.05052024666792,1.56187649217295,2.07319276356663,2.39911236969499,2.72504801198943,
3.37741951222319,4.05251086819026,4.38954709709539,4.72649271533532),.UNSPECIFIED.);
#685=CARTESIAN_POINT('',(10.86993,3.20309987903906,1.29345681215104));
#686=VERTEX_POINT('',#685);
#687=EDGE_CURVE('E11',#655,#686,#684,.T.);
#688=ORIENTED_EDGE('',*,*,#687,.T.);
#689=CARTESIAN_POINT('',(10.86993,3.20309987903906,1.29345681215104));
#690=CARTESIAN_POINT('',(10.8935842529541,3.18285348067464,1.34358685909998));
#691=CARTESIAN_POINT('',(10.9179308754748,3.16155586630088,1.39294673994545));
#692=CARTESIAN_POINT('',(10.9677116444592,3.11691854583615,1.49015514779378));
#693=CARTESIAN_POINT('',(10.9931455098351,3.09357936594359,1.53800405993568));
#694=CARTESIAN_POINT('',(11.0706135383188,3.0206090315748,1.67929702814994));
#695=CARTESIAN_POINT('',(11.1238495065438,2.96799537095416,1.77056035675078));
#696=CARTESIAN_POINT('',(11.2321253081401,2.85458341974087,1.94818870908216));
#697=CARTESIAN_POINT('',(11.2871773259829,2.79371344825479,2.03450018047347));
#698=CARTESIAN_POINT('',(11.3970908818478,2.66426087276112,2.20130360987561));
#699=CARTESIAN_POINT('',(11.4519523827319,2.59567684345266,2.28179448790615));
#700=CARTESIAN_POINT('',(11.5601067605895,2.45088443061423,2.43665194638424));
#701=CARTESIAN_POINT('',(11.6134005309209,2.37468050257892,2.51102205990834));
#702=CARTESIAN_POINT('',(11.717215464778,2.21464671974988,2.65323907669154));
#703=CARTESIAN_POINT('',(11.7677365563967,2.13081666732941,2.72108581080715));
#704=CARTESIAN_POINT('',(11.8645907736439,1.95598050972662,2.84933666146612));
#705=CARTESIAN_POINT('',(11.9109398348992,1.86500443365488,2.90976944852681));
#706=CARTESIAN_POINT('',(11.9984216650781,1.67592391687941,3.02262836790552));
#707=CARTESIAN_POINT('',(12.0395569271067,1.57782291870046,3.07505832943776));
#708=CARTESIAN_POINT('',(12.1298545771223,1.33623044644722,3.18925433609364));
#709=CARTESIAN_POINT('',(12.176113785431,1.18967340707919,3.24697940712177));
#710=CARTESIAN_POINT('',(12.2531511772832,0.886345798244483,3.34253208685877));
#711=CARTESIAN_POINT('',(12.2839378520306,0.729580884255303,3.38037060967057));
#712=CARTESIAN_POINT('',(12.327647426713,0.408975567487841,3.43396772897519));
#713=CARTESIAN_POINT('',(12.3404798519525,0.245103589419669,3.44961450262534));
#714=CARTESIAN_POINT('',(12.346772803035,-0.0835656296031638,3.45729674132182));
#715=CARTESIAN_POINT('',(12.3402360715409,-0.248362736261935,3.44933554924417));
#716=CARTESIAN_POINT('',(12.3097062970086,-0.560344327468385,3.41198152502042));
#717=CARTESIAN_POINT('',(12.2871409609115,-0.707888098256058,3.38434112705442));
#718=CARTESIAN_POINT('',(12.2278444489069,-0.995425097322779,3.31119780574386));
#719=CARTESIAN_POINT('',(12.1911127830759,-1.13541806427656,3.26569426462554));
#720=CARTESIAN_POINT('',(12.1030918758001,-1.41398661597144,3.15553154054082));
#721=CARTESIAN_POINT('',(12.051022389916,-1.55190001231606,3.08983411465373));
#722=CARTESIAN_POINT('',(11.9365869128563,-1.8147501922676,2.94317375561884));
#723=CARTESIAN_POINT('',(11.8742086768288,-1.93967125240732,2.86219265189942));
#724=CARTESIAN_POINT('',(11.7116860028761,-2.23029122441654,2.64666794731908));
#725=CARTESIAN_POINT('',(11.6073950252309,-2.38821403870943,2.50464969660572));
#726=CARTESIAN_POINT('',(11.4467050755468,-2.60235561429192,2.27412521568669));
#727=CARTESIAN_POINT('',(11.3923963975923,-2.66998200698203,2.19431033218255));
#728=CARTESIAN_POINT('',(11.2836244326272,-2.79769102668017,2.02896671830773));
#729=CARTESIAN_POINT('',(11.2291612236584,-2.85777694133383,1.94344050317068));
#730=CARTESIAN_POINT('',(11.121799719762,-2.97005001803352,1.76707840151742));
#731=CARTESIAN_POINT('',(11.0688955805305,-3.0222708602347,1.67626760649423));
#732=CARTESIAN_POINT('',(10.9919974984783,-3.09463803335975,1.53585638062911));
#733=CARTESIAN_POINT('',(10.9668060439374,-3.11773990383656,1.48841865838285));
#734=CARTESIAN_POINT('',(10.917492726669,-3.16193913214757,1.39205849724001));
#735=CARTESIAN_POINT('',(10.8933711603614,-3.18303593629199,1.34313565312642));
#736=CARTESIAN_POINT('',(10.86993,-3.20309987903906,1.29345681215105));
#737=B_SPLINE_CURVE_WITH_KNOTS('',3,(#689,#690,#691,#692,#693,#694,#695,#696,#697,#698,#699,
#700,#701,#702,#703,#704,#705,#706,#707,#708,#709,#710,#711,#712,#713,#714,#715,#716,#717,#718,
#719,#720,#721,#722,#723,#724,#725,#726,#727,#728,#729,#730,#731,#732,#733,#734,#735,#736),
.UNSPECIFIED.,.F.,.F.,(4,2,2,2,2,2,2,2,2,2,2,2,2,2,2,2,2,2,2,2,2,2,2,4),(0.,0.176991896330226,
0.35393830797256,0.707572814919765,1.06450173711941,1.42149671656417,1.77828416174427,
2.13508085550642,2.49045110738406,2.84565078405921,3.33603334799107,3.82614649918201,
4.31872063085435,4.81122501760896,5.26461214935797,5.71801496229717,6.2003901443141,
6.68334247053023,7.38910669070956,7.74244544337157,8.09562960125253,8.44725548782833,
8.62260738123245,8.79800755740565),.UNSPECIFIED.);
#738=CARTESIAN_POINT('',(10.86993,-3.20309987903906,1.29345681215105));
#739=VERTEX_POINT('',#738);
#740=EDGE_CURVE('E195',#686,#739,#737,.T.);
#741=ORIENTED_EDGE('',*,*,#740,.T.);
#742=CARTESIAN_POINT('',(11.0776912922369,-3.01286412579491,2.31602320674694));
#743=CARTESIAN_POINT('',(11.0570644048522,-3.03305702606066,2.23342246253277));
#744=CARTESIAN_POINT('',(11.0371654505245,-3.05212528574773,2.15036237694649));
#745=CARTESIAN_POINT('',(10.9990311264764,-3.08802482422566,1.98339698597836));
#746=CARTESIAN_POINT('',(10.9807954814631,-3.10485647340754,1.89949182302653));
#747=CARTESIAN_POINT('',(10.9461679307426,-3.13632048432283,1.73078200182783));
#748=CARTESIAN_POINT('',(10.9297782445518,-3.15095020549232,1.64597639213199));
#749=CARTESIAN_POINT('',(10.8990695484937,-3.17798993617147,1.47561970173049));
#750=CARTESIAN_POINT('',(10.8847510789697,-3.19039936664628,1.39006843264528));
#751=CARTESIAN_POINT('',(10.845926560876,-3.22367115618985,1.13709280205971));
#752=CARTESIAN_POINT('',(10.824590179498,-3.24143055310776,0.968745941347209));
#753=CARTESIAN_POINT('',(10.791837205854,-3.26840309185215,0.630405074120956));
#754=CARTESIAN_POINT('',(10.7804198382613,-3.27761690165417,0.460411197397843));
#755=CARTESIAN_POINT('',(10.7704653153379,-3.28563876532,0.181578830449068));
#756=CARTESIAN_POINT('',(10.7687589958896,-3.28700847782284,0.0729151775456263));
#757=CARTESIAN_POINT('',(10.7697144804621,-3.28623956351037,-0.144382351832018));
#758=CARTESIAN_POINT('',(10.7723764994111,-3.28410076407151,-0.25301622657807));
#759=CARTESIAN_POINT('',(10.7868514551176,-3.27242061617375,-0.578652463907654));
#760=CARTESIAN_POINT('',(10.8051591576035,-3.257610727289,-0.795222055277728));
#761=CARTESIAN_POINT('',(10.8580733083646,-3.21339785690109,-1.23252032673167));
#762=CARTESIAN_POINT('',(10.8932251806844,-3.18350461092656,-1.4531311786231));
#763=CARTESIAN_POINT('',(10.9557482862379,-3.12772080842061,-1.78000252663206));
#764=CARTESIAN_POINT('',(10.9782011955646,-3.10732177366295,-1.88820517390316));
#765=CARTESIAN_POINT('',(11.0259337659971,-3.06285328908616,-2.10319361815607));
#766=CARTESIAN_POINT('',(11.0512126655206,-3.03878482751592,-2.209979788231));
#767=CARTESIAN_POINT('',(11.0776912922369,-3.01286412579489,-2.31602320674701));
#768=B_SPLINE_CURVE_WITH_KNOTS('',3,(#742,#743,#744,#745,#746,#747,#748,#749,#750,#751,#752,
#753,#754,#755,#756,#757,#758,#759,#760,#761,#762,#763,#764,#765,#766,#767),.UNSPECIFIED.,.F.,
.F.,(4,2,2,2,2,2,2,2,2,2,2,2,4),(0.,0.26248946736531,0.524935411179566,0.787693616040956,
1.05052024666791,1.56187649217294,2.07319276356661,2.39911236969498,2.72504801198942,
3.37741951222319,4.05251086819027,4.3895470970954,4.72649271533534),.UNSPECIFIED.);
#769=EDGE_CURVE('E154',#739,#653,#768,.T.);
#770=ORIENTED_EDGE('',*,*,#769,.T.);
#771=EDGE_LOOP('',(#657,#688,#741,#770));
#772=FACE_BOUND('',#771,.T.);
#773=CARTESIAN_POINT('',(8.128,0.,5.77596));
#774=DIRECTION('',(0.,0.,1.));
#775=DIRECTION('',(1.,0.,0.));
#776=AXIS2_PLACEMENT_3D('',#773,#774,#775);
#777=CIRCLE('',#776,4.2164);
#778=CARTESIAN_POINT('',(12.3444,0.,5.77596));
#779=VERTEX_POINT('',#778);
#780=EDGE_CURVE('E308',#779,#779,#777,.T.);
#781=ORIENTED_EDGE('',*,*,#780,.T.);
#782=EDGE_LOOP('',(#781));
#783=FACE_BOUND('',#782,.T.);
#784=CARTESIAN_POINT('',(8.128,0.,-5.77596));
#785=DIRECTION('',(0.,0.,-1.));
#786=DIRECTION('',(0.,1.,0.));
#787=AXIS2_PLACEMENT_3D('',#784,#785,#786);
#788=CIRCLE('',#787,4.21640000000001);
#789=CARTESIAN_POINT('',(8.128,4.21640000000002,-5.77596));
#790=VERTEX_POINT('',#789);
#791=EDGE_CURVE('E317',#790,#790,#788,.T.);
#792=ORIENTED_EDGE('',*,*,#791,.T.);
#793=EDGE_LOOP('',(#792));
#794=FACE_BOUND('',#793,.T.);
#795=ADVANCED_FACE('F184',(#772,#783,#794),#602,.F.);
#796=CARTESIAN_POINT('',(12.3444,0.,5.77596));
#797=DIRECTION('',(0.,0.,-1.));
#798=DIRECTION('',(-1.,0.,0.));
#799=AXIS2_PLACEMENT_3D('',#796,#797,#798);
#800=PLANE('',#799);
#801=ORIENTED_EDGE('',*,*,#780,.F.);
#802=EDGE_LOOP('',(#801));
#803=FACE_BOUND('',#802,.T.);
#804=CARTESIAN_POINT('',(8.128,0.,5.77596));
#805=DIRECTION('',(0.,0.,1.));
#806=DIRECTION('',(1.,0.,0.));
#807=AXIS2_PLACEMENT_3D('',#804,#805,#806);
#808=CIRCLE('',#807,4.93618496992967);
#809=CARTESIAN_POINT('',(13.0641849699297,0.,5.77596));
#810=VERTEX_POINT('',#809);
#811=EDGE_CURVE('E311',#810,#810,#808,.T.);
#812=ORIENTED_EDGE('',*,*,#811,.T.);
#813=EDGE_LOOP('',(#812));
#814=FACE_BOUND('',#813,.T.);
#815=ADVANCED_FACE('F189',(#803,#814),#800,.F.);
#816=CARTESIAN_POINT('',(8.128,0.,12.7));
#817=DIRECTION('',(0.,0.,1.));
#818=DIRECTION('',(1.,0.,0.));
#819=AXIS2_PLACEMENT_3D('',#816,#817,#818);
#820=CONICAL_SURFACE('',#819,5.1435,0.0299323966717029);
#821=ORIENTED_EDGE('',*,*,#811,.F.);
#822=EDGE_LOOP('',(#821));
#823=FACE_BOUND('',#822,.T.);
#824=ORIENTED_EDGE('',*,*,#126,.T.);
#825=EDGE_LOOP('',(#824));
#826=FACE_BOUND('',#825,.T.);
#827=ADVANCED_FACE('F229',(#823,#826),#820,.F.);
#828=CARTESIAN_POINT('',(12.3444,0.,-5.77596));
#829=DIRECTION('',(0.,0.,1.));
#830=DIRECTION('',(0.,-1.,0.));
#831=AXIS2_PLACEMENT_3D('',#828,#829,#830);
#832=PLANE('',#831);
#833=ORIENTED_EDGE('',*,*,#791,.F.);
#834=EDGE_LOOP('',(#833));
#835=FACE_BOUND('',#834,.T.);
#836=CARTESIAN_POINT('',(8.128,0.,-5.77596));
#837=DIRECTION('',(0.,0.,-1.));
#838=DIRECTION('',(0.,1.,0.));
#839=AXIS2_PLACEMENT_3D('',#836,#837,#838);
#840=CIRCLE('',#839,4.93618496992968);
#841=CARTESIAN_POINT('',(8.128,4.93618496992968,-5.77596));
#842=VERTEX_POINT('',#841);
#843=EDGE_CURVE('E320',#842,#842,#840,.T.);
#844=ORIENTED_EDGE('',*,*,#843,.T.);
#845=EDGE_LOOP('',(#844));
#846=FACE_BOUND('',#845,.T.);
#847=ADVANCED_FACE('F226',(#835,#846),#832,.F.);
#848=CARTESIAN_POINT('',(8.128,0.,-12.7));
#849=DIRECTION('',(0.,0.,-1.));
#850=DIRECTION('',(0.,1.,0.));
#851=AXIS2_PLACEMENT_3D('',#848,#849,#850);
#852=CONICAL_SURFACE('',#851,5.1435,0.0299323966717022);
#853=ORIENTED_EDGE('',*,*,#843,.F.);
#854=EDGE_LOOP('',(#853));
#855=FACE_BOUND('',#854,.T.);
#856=ORIENTED_EDGE('',*,*,#227,.T.);
#857=EDGE_LOOP('',(#856));
#858=FACE_BOUND('',#857,.T.);
#859=ADVANCED_FACE('F213',(#855,#858),#852,.F.);
#860=CARTESIAN_POINT('',(39.44747,0.,0.));
#861=DIRECTION('',(1.,0.,0.));
#862=DIRECTION('',(0.,0.,-1.));
#863=AXIS2_PLACEMENT_3D('',#860,#861,#862);
#864=CYLINDRICAL_SURFACE('',#863,3.45439999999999);
#865=CARTESIAN_POINT('',(12.77747,0.,0.));
#866=DIRECTION('',(1.,0.,0.));
#867=DIRECTION('',(0.,0.,-1.));
#868=AXIS2_PLACEMENT_3D('',#865,#866,#867);
#869=CIRCLE('',#868,3.45439999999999);
#870=CARTESIAN_POINT('',(12.77747,0.,-3.45439999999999));
#871=VERTEX_POINT('',#870);
#872=EDGE_CURVE('E329',#871,#871,#869,.T.);
#873=ORIENTED_EDGE('',*,*,#872,.T.);
#874=EDGE_LOOP('',(#873));
#875=FACE_BOUND('',#874,.T.);
#876=CARTESIAN_POINT('',(10.86993,0.,0.));
#877=DIRECTION('',(1.,0.,0.));
#878=DIRECTION('',(0.,0.,-1.));
#879=AXIS2_PLACEMENT_3D('',#876,#877,#878);
#880=CIRCLE('',#879,3.45439999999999);
#881=EDGE_CURVE('E50',#739,#653,#880,.T.);
#882=ORIENTED_EDGE('',*,*,#881,.F.);
#883=ORIENTED_EDGE('',*,*,#740,.F.);
#884=EDGE_CURVE('E326',#655,#686,#880,.T.);
#885=ORIENTED_EDGE('',*,*,#884,.F.);
#886=ORIENTED_EDGE('',*,*,#656,.F.);
#887=EDGE_LOOP('',(#882,#883,#885,#886));
#888=FACE_BOUND('',#887,.T.);
#889=ADVANCED_FACE('F208',(#875,#888),#864,.F.);
#890=CARTESIAN_POINT('',(10.86993,0.,0.));
#891=DIRECTION('',(1.,0.,0.));
#892=DIRECTION('',(0.,0.,-1.));
#893=AXIS2_PLACEMENT_3D('',#890,#891,#892);
#894=CONICAL_SURFACE('',#893,3.45439999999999,1.02974425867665);
#895=ORIENTED_EDGE('',*,*,#884,.T.);
#896=ORIENTED_EDGE('',*,*,#687,.F.);
#897=EDGE_LOOP('',(#895,#896));
#898=FACE_BOUND('',#897,.T.);
#899=ADVANCED_FACE('F212',(#898),#894,.F.);
#900=ORIENTED_EDGE('',*,*,#881,.T.);
#901=ORIENTED_EDGE('',*,*,#769,.F.);
#902=EDGE_LOOP('',(#900,#901));
#903=FACE_BOUND('',#902,.T.);
#904=ADVANCED_FACE('F221',(#903),#894,.F.);
#905=CARTESIAN_POINT('',(12.77747,3.45439999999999,0.));
#906=DIRECTION('',(-1.,0.,0.));
#907=DIRECTION('',(0.,0.,1.));
#908=AXIS2_PLACEMENT_3D('',#905,#906,#907);
#909=PLANE('',#908);
#910=ORIENTED_EDGE('',*,*,#872,.F.);
#911=EDGE_LOOP('',(#910));
#912=FACE_BOUND('',#911,.T.);
#913=CARTESIAN_POINT('',(12.77747,0.,0.));
#914=DIRECTION('',(1.,0.,0.));
#915=DIRECTION('',(0.,0.,-1.));
#916=AXIS2_PLACEMENT_3D('',#913,#914,#915);
#917=CIRCLE('',#916,3.96874999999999);
#918=CARTESIAN_POINT('',(12.77747,0.,-3.96874999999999));
#919=VERTEX_POINT('',#918);
#920=EDGE_CURVE('E332',#919,#919,#917,.T.);
#921=ORIENTED_EDGE('',*,*,#920,.T.);
#922=EDGE_LOOP('',(#921));
#923=FACE_BOUND('',#922,.T.);
#924=ADVANCED_FACE('F215',(#912,#923),#909,.F.);
#925=CARTESIAN_POINT('',(39.44747,0.,0.));
#926=DIRECTION('',(1.,0.,0.));
#927=DIRECTION('',(0.,0.,-1.));
#928=AXIS2_PLACEMENT_3D('',#925,#926,#927);
#929=CYLINDRICAL_SURFACE('',#928,3.96875);
#930=ORIENTED_EDGE('',*,*,#369,.T.);
#931=EDGE_LOOP('',(#930));
#932=FACE_BOUND('',#931,.T.);
#933=ORIENTED_EDGE('',*,*,#920,.F.);
#934=EDGE_LOOP('',(#933));
#935=FACE_BOUND('',#934,.T.);
#936=ADVANCED_FACE('F337',(#932,#935),#929,.F.);
#937=CLOSED_SHELL('',(#46,#113,#166,#190,#214,#249,#273,#290,#304,#316,#344,#356,#384,#545,#565,
#585,#597,#795,#815,#827,#847,#859,#889,#899,#904,#924,#936));
#938=MANIFOLD_SOLID_BREP('B2',#937);
#939=ADVANCED_BREP_SHAPE_REPRESENTATION('',(#18,#938),#14);
#940=SHAPE_DEFINITION_REPRESENTATION(#9,#939);
ENDSEC;
END-ISO-10303-21;
